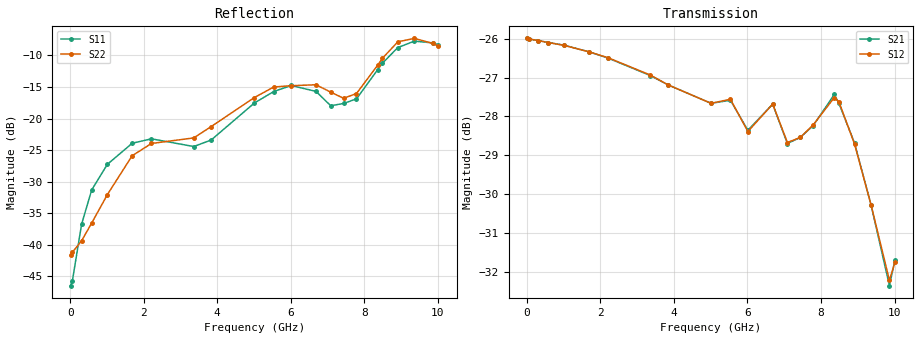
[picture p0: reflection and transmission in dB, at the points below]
! Device ID: PE43705
! Serial: 1
! Insertion: A
! Impedance: 50 ohm
! Temp: 25C
! VDD: 3.400V
! Attenuation Step: 25.00dB
#  Hz  S  RI  R  50
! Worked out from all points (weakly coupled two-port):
!   401 points, 10 MHz to 10.01 GHz, reference 50 ohm
!   highest |S21| = -25.99 dB at 10 MHz (marker M1); lowest = -32.4 dB at 9.86 GHz (marker M2)
!   lowest |S11| = -46.5 dB at 10 MHz (marker M3), VSWR 1.01, Z = 49.5 + j0.05 ohm
!   |S11| at or under -10 dB: start of sweep to 8.671 GHz
!   |S22| runs from -41.6 to -7.2 dB; largest |S21 - S12| = 0.00069
!   S11 on the Smith chart (normalised r, x): 10 MHz: 0.99, +0.00; 7.435 GHz: 0.82, +0.16; 8.485 GHz: 0.84, +0.49; 9.36 GHz: 0.55, +0.49; 10.01 GHz: 0.49, +0.27
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1e7  -0.00471 0.000505  0.0502 -0.000172  0.0502 -0.000125  0.00828 0.000342
6e7  -0.00449 0.00262  0.0501 -0.000866  0.0501 -0.000862  0.00854 0.00172
3.1e8  -0.00673 0.0129  0.0497 -0.00411  0.0497 -0.00409  0.00613 0.00883
5.85e8  -0.0147 0.0229  0.049 -0.00759  0.049 -0.00756  -0.00141 0.0148
1.01e9  -0.0335 0.0275  0.0475 -0.0128  0.0475 -0.0127  -0.0203 0.0145
1.685e9  -0.0612 0.0176  0.0439 -0.02  0.0439 -0.02  -0.0507 0.00195
2.21e9  -0.069 0.00295  0.0402 -0.025  0.0402 -0.0251  -0.0626 -0.0103
3.36e9  -0.0598 0.00482  0.0303 -0.0332  0.0304 -0.0332  -0.0702 -0.00176
3.835e9  -0.0624 0.0261  0.0261 -0.0351  0.0261 -0.0351  -0.0848 0.0165
5.01e9  -0.0992 0.0883  0.0171 -0.0377  0.0171 -0.0377  -0.1284 0.0711
5.535e9  -0.1285 0.1013  0.0127 -0.0398  0.0128 -0.0399  -0.1506 0.0944
6.01e9  -0.1513 0.1025  0.00876 -0.0372  0.00898 -0.037  -0.1506 0.1023
6.685e9  -0.1417 0.0825  0.00493 -0.041  0.00505 -0.041  -0.1516 0.1063
7.085e9  -0.1083 0.0649  -0.00166 -0.0367  -0.00195 -0.0368  -0.1138 0.1151
7.435e9  -0.0894 0.0966  -0.00106 -0.0374  -0.00064 -0.0374  -0.0739 0.1244
7.785e9  -0.0437 0.1363  -0.00156 -0.0387  -0.00157 -0.0388  -0.0417 0.1521
8.36e9  -0.00903 0.2433  -0.0119 -0.0408  -0.0115 -0.0405  -0.0184 0.2635
8.485e9  -0.0153 0.273  -0.0142 -0.0389  -0.0142 -0.0391  -0.0226 0.2982
8.91e9  -0.0713 0.3579  -0.0187 -0.0317  -0.0185 -0.0317  -0.0752 0.3981
9.36e9  -0.1709 0.3733  -0.0174 -0.0252  -0.0174 -0.0252  -0.1577 0.4019
9.86e9  -0.2778 0.2842  -0.00887 -0.0224  -0.00891 -0.0228  -0.2674 0.2887
1.001e10  -0.302 0.2368  -0.006 -0.0253  -0.00611 -0.0251  -0.2951 0.2283
